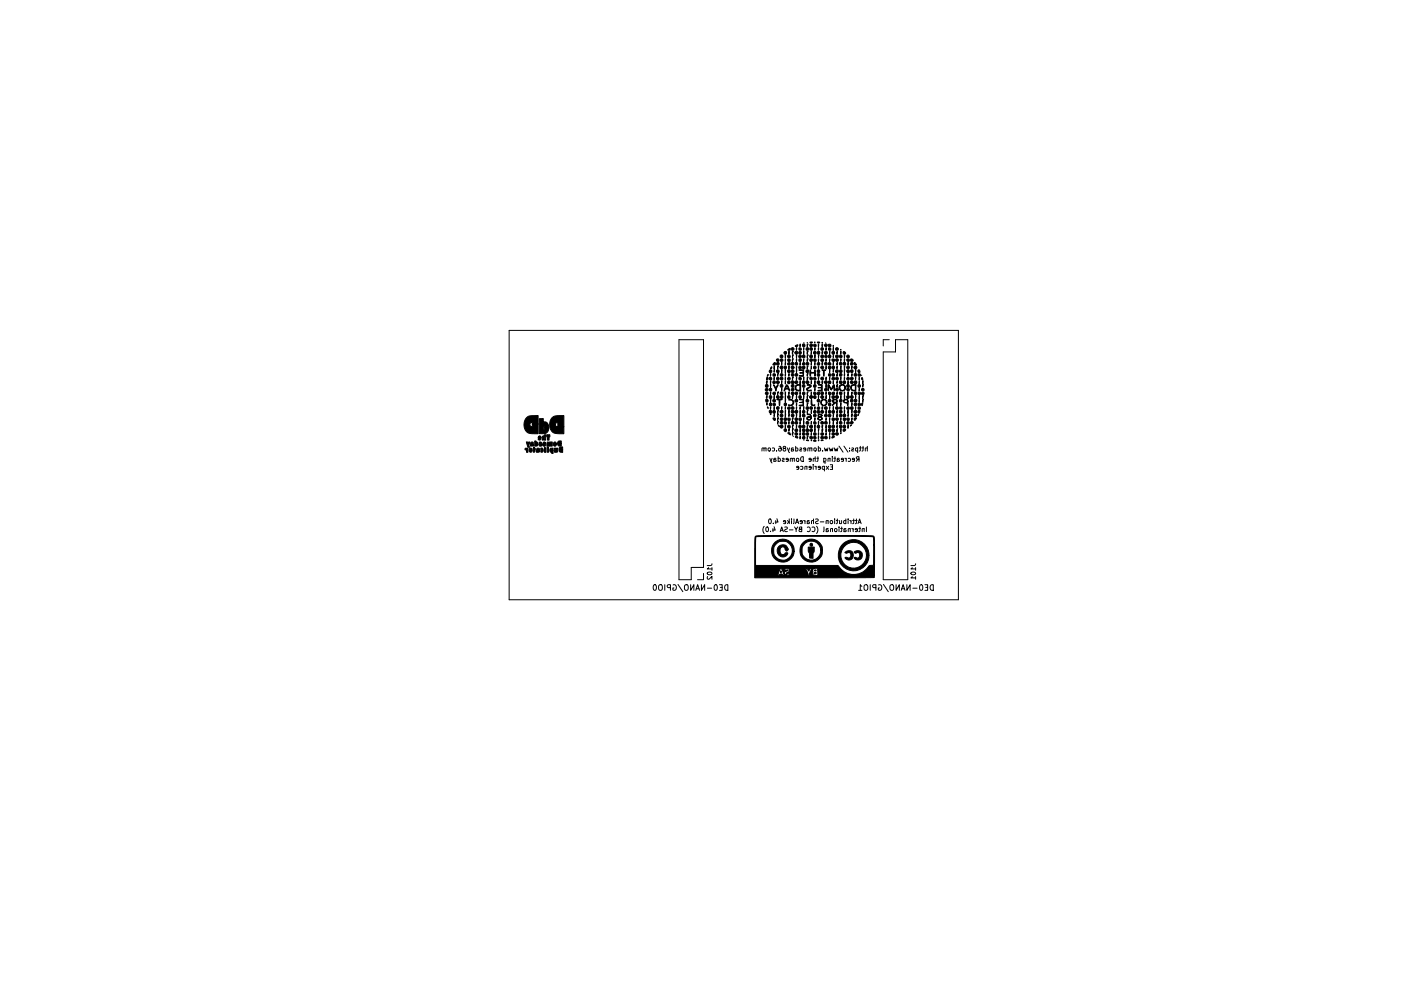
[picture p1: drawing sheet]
<svg xmlns="http://www.w3.org/2000/svg" width="297mm" height="210mm" viewBox="0 0 297 210" stroke-linecap="round" stroke-linejoin="round" font-family="sans-serif">
<g fill="none" stroke="#000" stroke-width=".21">
<path d="M107.9 70.1h95.3v57.1h-95.3zM144 72.1h5.2v48.3h-2.6v2.6h-2.6zM188.5 72.1h-1.2v1.3M189.9 72.1h2.6v50.9h-5.2v-48.3h2.6zM162 95.2l-.4-.1v.6M162.4 95.1h-.4v.6M162.4 95v.7M162.9 95.1h.4v.5h-.4zM163.2 97.2l.5 1M163.7 97.2l-.2 .7M163.7 95.1l.3-.1 .2 .2-.1 .4h-.4M164.1 97.5l.5 .2-.2 .2-.3-.1"/>
<path d="M164.5 97.3h-.4v.6M164.6 95.6v.1M165 97.3l.3-.1 .2 .2-.1 .4h-.4M165 96.9v1M165.2 94.7l.4 .2v.6l-.1 .2-.4-.1 .1-.5h.3l.1 .2M165.9 97.3l.4 .1-.4 .2v.2h.4M166.2 95.1l-.2 .2 .2 .4 .4-.1v-.3l-.5-.3v-.3l.5 .1-.2 .3M166.9 95l.5 1M167.1 97.6l-.5-.1 .1-.2 .3-.1 .1 .2v.4h-.4M167.4 95l-.2 .7M168 97.4l-.4-.1v.6M168.2 95.1l-.3-.1-.1 .2v.5h.3l.1-.3-.4-.1"/>
<path d="M168.4 97.3h-.4v.6M168.4 97.2v.7M168.7 94.7v.9h.4v-.5h-.4M168.9 97.3h.4v.5h-.4zM169.4 99.3l-.5-.1v-.2l.3-.1 .2 .2-.1 .4h-.4M169.6 95.1l.4 .1-.4 .2v.2h.4M169.7 99l.3-.1 .2 .2-.1 .4h-.4M169.8 97l.5-.1v1a.52 .52 0 0 1-.5-.3 .52 .52 0 0 1 0-.6zM170.8 95.4l-.4-.1v-.2l.3-.1 .1 .2v.4h-.4M171.1 99h-.4l-.1 .6M171.1 98.9v.7M171.7 95.2l-.4-.1v.6"/>
<path d="M172 97.6l-.5-.1 .1-.2 .2-.1 .2 .2-.1 .4h-.3M172 99.3l-.5-.1 .1-.2 .2-.1 .2 .2-.1 .4h-.3M172.1 95.1h-.4v.6M172.1 95v.7M172.4 98.6v.1M172.4 98.9v.7M172.6 95.1h.4v.5h-.4zM172.7 98.9l.3 .2M172.8 97.3h-.3l-.1 .6M172.8 96.9v1M173 98.9v.7M173.2 97.2h.4"/>
<path d="M173.4 96.9v.9l-.2 .1M173.5 94.7v.9h.4v-.5h-.4M173.9 99.3l-.4-.1v-.2l.3-.1 .1 .2v.4h-.4M174.4 95.6v.1M174.6 97.2v.8l.2 .2h.3M174.6 97.3l.3-.1 .2 .2-.1 .4h-.4M174.8 99l-.3-.1-.2 .2 .1 .4h.4M174.8 95l.2 .7 .2-.5 .2 .5 .2-.7M174.8 98.9v1M175.2 98.9l.5 .7M175.7 98.9l-.5 .7M175.8 95l.2 .7 .2-.5 .2 .5 .2-.7"/>
<path d="M176 97.3h-.4v.6M176 97.2v.7M176 98.6h.5v1h-.5M176.2 99.1h.3M176.5 96.9v.1M176.5 97.2v.7M176.8 97.2h.4M176.9 95l.2 .7 .2-.5 .2 .5 .1-.7M177 96.9v.9l-.2 .1M177.5 97.5l.5 .2-.2 .2-.3-.1M177.9 94.6l.8 1.3M177.9 97.3h-.3l-.1 .6"/>
<path d="M178.8 97.6l-.4-.1v-.2l.3-.1 .1 .2v.4h-.4M178.9 94.6l.9 1.3M179.1 97.2l.3 .2M179.4 97.2v.7M179.8 97.3l.3-.1 .2 .2-.1 .4h-.4M180.1 95.6v.1M180.1 95.1v.1M180.6 95.1l.4 .1-.4 .2v.2h.4M181.2 97.6l-.5-.1v-.2l.3-.1 .2 .2-.1 .4h-.4M181.8 95.1l-.2-.1-.2 .2 .1 .4h.3M181.8 95v1M181.9 97.4l-.3 .5"/>
<path d="M182.1 97.4h-.5v-.4l.5-.1v1M182.2 95h.4M182.4 94.7v.9l-.2 .1M182.7 95h.4M183 94.7v.9l-.3 .1M183.9 95.1h-.4v.6M183.9 94.7v1M150.9 119.6l-.1 .3-.9 .1M162 111.7a1.15 1.15 0 0 0 0 1.5M162.5 111.9l.1-.1a.49 .49 0 0 1 .4 .5 .49 .49 0 0 1-.5 .5l-.1-.4zM163.1 110.2l.1-.1a.49 .49 0 0 1 .4 .5 .49 .49 0 0 1-.5 .5l-.1-.4zM163.4 112.7v.1"/>
<path d="M163.9 112.1v.7M164 111v.1M164.1 111.8l.3 .7h-.7M164.5 110.4v.7M164.7 110.1l.3 .7h-.7M165.4 112.8l.3-1 .4 1M165.5 112.5h.5M166.4 111.9h.5a.42 .42 0 0 1-.5 .5l.1 .4h.4M166.6 110.8l-.5-.1v-.2l.3-.1 .2 .2-.1 .5h-.4M167 110.4l.3 .4M167.2 110.7l-.2 .4M167.3 110.1v1"/>
<path d="M167.4 112.4h.7M167.8 110.1v.1M167.8 110.4v.7M168.3 110.1v.9l-.1 .1M168.5 111.8l.3 .5 .3-.5M168.7 111.1l.3-1 .3 1M168.8 110.8h.4M168.8 112.3v.5M169.6 112.3l-.2 .2 .2 .3h.4v-1l-.5 .1 .1 .3 .4 .1M170.1 110.8l-.5-.1 .1-.2 .3-.1 .1 .2v.5h-.4M170.4 110.4l.3 .2M170.7 110.4v.7"/>
<path d="M171.1 110.7l.5 .2-.1 .2h-.4M171.2 111.9a.44 .44 0 0 1 .6 .4 .44 .44 0 0 1-.6 .4M171.6 110.5h-.4l-.1 .6M172.2 111.9a.44 .44 0 0 1 .6 .4 .44 .44 0 0 1-.6 .4M172.5 110.5h-.4v.6M172.5 110.1v1M172.9 110.2h.5a.42 .42 0 0 1-.4 .5v.4h.5M173.1 111.7a1.15 1.15 0 0 1 0 1.5M173.9 110.7h.8M174.7 111.8v.9l-.1 .1M175.2 112.4l.4 .2-.1 .2h-.3M175.6 110.5h-.4l-.1 .6"/>
<path d="M175.6 110.4v.7M175.6 112.2h-.4v.6M176.1 110.5h.4l-.1 .6-.3-.1zM176.5 112.2h-.4v.6M176.5 112.1v.7M177 110.1v.1M177 110.4v.7M177 112.2h.4v.6l-.4-.1zM177.3 110.4h.4M177.5 110.1v.9l-.2 .1M177.9 111.8v.1M177.9 112.1v.7"/>
<path d="M178 110.4v.7M178.2 112.1h.4M178.4 110.4v.7l-.4-.1M178.5 111.8v.9l-.3 .1M178.9 112.4l.5 .2-.1 .2h-.4M179.3 110.5l-.2-.1-.2 .2 .1 .5h.3M179.3 110.1v1M179.4 112.2h-.4l-.1 .6M179.8 110.1v.1M179.8 110.4v.7M180.1 110.4l.3 .2M180.3 112.2h-.4l-.1 .6"/>
<path d="M180.3 112.1v.7M180.4 110.4v.7M180.6 112.1l.3 .2M180.8 110.4h.3M180.9 112.1v.7M181 110.1v.9l-.2 .1M181.3 110.4h.4M181.6 110.1v.9l-.3 .1M181.8 112.5l-.5-.1 .1-.2 .2-.1 .2 .2-.1 .5h-.3M181.9 111.1l.3-1 .4 1M182 110.8h.5M182.1 112.1h.4"/>
<path d="M182.3 111.8v.9l-.2 .1M183.2 112.2h-.4v.6M183.2 112.1v.7M183.7 111.8v1M194.1 119.6l-.1 .3-.9 .1M138.6 124.2l.2-.1a.64 .64 0 0 1 .4 .6 .64 .64 0 0 1-.4 .6l-.3-.5zM139.7 124.2l.2-.1a.4 .4 0 0 1 .5 .4v.4a.4 .4 0 0 1-.4 .4 .4 .4 0 0 1-.4-.4zM140.9 124.1v1.2M142.1 124.7l-.5-.1-.1-.4 .6-.1v1.2M142.7 124.1a.55 .55 0 0 1 .7 .6 .55 .55 0 0 1-.7 .4v-.4h.2M143.7 124l1.1 1.5M145.2 124.2l.2-.1a.4 .4 0 0 1 .5 .4v.4a.4 .4 0 0 1-.4 .4 .4 .4 0 0 1-.4-.4z"/>
<path d="M146.4 124.1v1.2l.7-1.2v1.2M147.5 125.3l.4-1.2 .4 1.2M147.6 124.9h.6M148.7 124.1v1.2l.7-1.2v1.2M149.2 121.7v1.3h-1.3M150 124.8h.9M150 121.5a.49 .49 0 0 1 .6-.2 .49 .49 0 0 1 .3 .5 .49 .49 0 0 1-.6 .2 .49 .49 0 0 1-.3-.5zM150 122.3l-.1 .4 .3 .2 .7-.6v.6M150.2 120.4l-.3 .3h1M150.9 120.4v.6M151.5 124.2l.2-.1a.64 .64 0 0 1 .4 .6 .64 .64 0 0 1-.4 .6l-.3-.5zM152.5 124.1h.6v1.2h-.6"/>
<path d="M152.7 124.6h.4M153.7 124.2l.6-.1v1.2a.63 .63 0 0 1-.6-.4 .63 .63 0 0 1 0-.7zM182 125.3h.7M182.7 124.4l-.3-.3v1.2M183.2 124.2l.3-.1a.4 .4 0 0 1 .5 .4v.4a.4 .4 0 0 1-.4 .4 .4 .4 0 0 1-.4-.4zM184.5 124.1v1.2M185.7 124.7l-.6-.1v-.4l.6-.1v1.2M186.3 124.1a.55 .55 0 0 1 .7 .6 .55 .55 0 0 1-.8 .4v-.4h.2M187.3 124l1 1.5M188.7 124.2l.3-.1a.4 .4 0 0 1 .5 .4v.4a.4 .4 0 0 1-.4 .4 .4 .4 0 0 1-.4-.4zM190 124.1v1.2l.7-1.2v1.2M191.1 125.3l.4-1.2 .4 1.2"/>
<path d="M191.2 124.9h.6M192.3 124.1v1.2l.7-1.2v1.2M193.2 121.5a.49 .49 0 0 1 .5-.2 .49 .49 0 0 1 .4 .5 .49 .49 0 0 1-.6 .2 .49 .49 0 0 1-.3-.5zM193.4 120.4l-.3 .3h1M193.4 122.3l-.3 .3h1M193.5 124.8h.9M194.1 120.4v.6M194.1 122.3v.6M195.1 124.2l.1-.1a.64 .64 0 0 1 .5 .6 .64 .64 0 0 1-.5 .6l-.2-.5zM196.1 124.1h.6v1.2h-.6M196.3 124.6h.4M197.3 124.2l.6-.1v1.2a.63 .63 0 0 1-.7-.4 .63 .63 0 0 1 .1-.7z"/>
</g>
<g fill="#000" stroke="#000" stroke-width=".21">
<path d="M162.8 79.4l-.1 .4zM163.4 79.2v.6zM163.5 77.9l.1-.1v.3l-.3 .2zM164.1 77.7v.7zM164.2 78.4l-.1 .6zM164.1 77l.2-.1 .1 .5h-.5zM164.9 79.3h.2l-.2 .5zM164.9 77.7h.2l-.2 .6zM165.8 76.9l-.1 .6zM165.7 78.4v.7zM166.5 79.2v.6zM166.5 76.9v.6z"/>
<path d="M166.5 76.1v.6zM166.5 78.4v.7zM166.5 75.3v.7zM167.1 75.4h.4l-.1 .5-.4-.1zM167.1 77h.4v.4l-.5-.1zM167.3 79.2l-.1 .6zM167.3 77.7v.7zM167.3 74.5v.7zM167.1 74.2l.4-.3v.4h-.4zM168 76.2l.2-.1-.2 .6zM168 74.5h.2l-.2 .7zM168.1 75.3h.1l-.2 .7z"/>
<path d="M168.9 76.1v.6zM168.9 73.7v.6zM168.9 77.6v.7zM168.9 78.4v.7zM168.9 75.3v.7zM168.6 73.4l.5-.3a.31 .31 0 0 1-.1 .4 .31 .31 0 0 1-.4-.1zM169.4 78.5h1v1.3h-1l.8-.2v-.4l-.7-.1 .6-.1 .2-.3zM169.4 76.2l.5 .1-.1 .4-.4-.1zM169.7 76.9l-.1 .6zM169.7 73l-.1 .6zM170.2 75.4h.4v.5l-.4-.1zM170.2 77h.4v.4l-.5-.1z"/>
<path d="M170.4 76.1v.6zM170.4 73.7v.6zM170.4 72.8h.1zM170.4 74.5v.7zM171.1 72.7l.1 .1zM171.2 79.3h.1l-.1 .5zM171.2 76.2l.1-.1-.1 .6zM171.2 73h.1l-.1 .6zM171.2 77.7h.1l-.1 .6zM171.2 74.5h.1l-.1 .7zM171.2 75.3h.2l-.2 .7zM171.8 78.5a.5 .5 0 0 0 .5 .5 .5 .5 0 0 0 .5-.5v1.3l-.1-.6h-.8l-.1 .6z"/>
<path d="M171.8 72.6h.5l-.3 .2zM172 76.9v.6zM172 77.6v.7zM172 74.5v.7zM172.8 76.9v.6zM172.8 73.7v.6zM172.7 72.5l.1 .3zM172.8 75.3v.7zM173.3 72.6l.5 .1-.3 .1zM173.4 77h.3v.4l-.4-.1zM173.5 76.1v.6zM173.5 73.7v.6z"/>
<path d="M173.5 73v.6zM173.5 77.7v.7zM173.6 75.3l-.1 .6zM174.2 72.7h.2zM174.3 76.9h.1l-.1 .6zM174.3 73.1h.1l-.1 .5zM174.3 74.6l.1-.1v.2l-.1 .4zM174.3 78.5h.8l-.3 .1-.1 1.2-.1-1.2zM175.2 76.1l-.1 .6zM175.2 73.7l-.1 .6zM175.1 77.7v.7zM175.9 76.1v.6z"/>
<path d="M175.9 78.4v.7zM175.9 74.5v.7zM176.6 73.3l.1 .2zM176.7 76.9v.6zM176.7 73.8v.6zM176.7 78.4v.6zM176.7 75.3v.6zM177.5 77.7l.1-.1-.1 .6zM177.5 74.6l.1-.1-.1 .6zM177.5 79.3v.5zM177.5 76.9v.6zM178.3 76.1v.6z"/>
<path d="M178.3 74.5v.7zM178.3 74.1v.2zM178.3 77.7v.7zM179.1 79.2l-.1 .6zM179.1 76.1l-.1 .6zM179 78.4v.7zM179 77.7v.7zM179 75.3v.7zM179.8 79.2v.6zM179.8 76.9v.6zM180.6 79.3v.5zM180.6 77.7v.5z"/>
<path d="M181.2 76.9l.4 .5h-.4zM181.4 78.4v.7zM182 78.5l.3 .1v.4l-.1 .1-.3-.2zM111.6 93.8h.3l.1 .2 .3-.2-.2 .7 .2 .4h-.4zM111.3 95.2l.6-.1v.9h-.3v-.5a.21 .21 0 0 1-.2-.1 .21 .21 0 0 1-.1-.2zM112.3 95.2l.3-.1 .2 .2v.2l-.3-.1v.2l.3-.1a.37 .37 0 0 1-.5 .4 .37 .37 0 0 1-.1-.6zM112.6 93.9a.28 .28 0 0 1 .3-.1 .28 .28 0 0 1 .2 .3l-.3 .1 .3 .2h-.3h.3v.2h-.6zM113.2 94.8l.3 .5a.44 .44 0 0 1-.4 .6l-.1-.7zM111.7 88.6a1.75 1.75 0 0 1 1.5-.4h.9v1.8h-1.2l-.1-.3a.39 .39 0 0 0-.5 .4 .39 .39 0 0 0 .5 .3l.1-.4h1.2v2a3.1 3.1 0 0 1-2.6-.5 2.32 2.32 0 0 1 .2-2.9zM113.4 93.6h.2l.1 .2 .3 .1 .1 .4-.4-.2v.3l.4-.1-.2 .3-.5 .1zM113.9 95.1a.29 .29 0 0 1 .3 0 .29 .29 0 0 1 .2 .3h-.3l.3 .3h-.3h.3l-.1 .2-.6 .1zM114.2 92.6l.3-.1 .2 .2-.4 .1h.4a.35 .35 0 0 1-.1 .5 .35 .35 0 0 1-.5-.2h.3l-.3-.2z"/>
<path d="M114.3 93.8a.33 .33 0 0 1 .5 .1 .33 .33 0 0 1-.2 .5h.2a.3 .3 0 0 1-.3 .3 .3 .3 0 0 1-.3-.4 .3 .3 0 0 1 .4-.2zM114.7 95.1a.42 .42 0 0 1 .5 .4 .42 .42 0 0 1-.5 .4l-.1-.3 .3-.1a.21 .21 0 0 1-.3-.2 .21 .21 0 0 1 .1-.2zM114.3 88.8h.9v.8a.95 .95 0 0 1 1.2 1.2h-.9l-.2-.3-.1 .6h.2l.1-.3h.9a1.18 1.18 0 0 1-1.5 1.2h-.6zM115.3 93.8h.2l.2 .3-.4-.1v.1h.4a.35 .35 0 0 1-.1 .5 .35 .35 0 0 1-.5-.2l.3-.1h-.3zM115.4 95.1h.3v.9h-.3zM115 92.5l.4 .1v-.3l.3-.1v1.2h-.3l-.1-.7-.1 .7h-.2zM115.5 94.9h.1l-.1 .1zM115.9 92.2h.7l-.2 1.2h-.3zM116 94.8h.3v1.1h-.3zM116.1 93.8l.3 .1 .7-.1v.9h-.3l-.1-.7-.1 .7h-.2l-.1-.7-.1 .7h-.2zM116.7 95.1h.6v.4l-.4-.1v.1v.2l.4-.2v.7h-.3v-.2a.5 .5 0 0 1-.4-.3 .5 .5 0 0 1 .1-.6zM117.5 93.8l.4 .1 .1 .3-.4-.1v.1h.4v.1a.37 .37 0 0 1-.6 .3 .37 .37 0 0 1 0-.6z"/>
<path d="M117.5 95.1h.4v.6l.1-.6h.2l-.1 .8h-.5zM118.3 93.7l.7-.1v.5l-.4-.1-.1 .1 .1 .1 .4-.1v.6a.6 .6 0 0 1-.7-.3 .6 .6 0 0 1 0-.7zM117.1 88.6a2.99 2.99 0 0 1 2.4-.4v2.4h-1.2v-.9a.42 .42 0 0 0-.5 .5 .42 .42 0 0 0 .5 .4h1.2v1.4a3.2 3.2 0 0 1-2.5-.5 2.39 2.39 0 0 1 .1-2.9zM118.6 95l.7-.2v.6h-.3l-.1-.2-.1 .2 .1 .1 .1-.1h.3v.6l-.4-.1a.58 .58 0 0 1-.3-.9zM162.6 85.6v-.1v.5zM162.6 83.9v.6zM162.6 80.8v.6zM162.6 80l.2 .2 .1 .2-.3 .2-.1-.1zM162.7 86.3l.1 .4zM163.2 85.6l.4 .1-.1 .4-.4-.1zM163.2 82.4l.4 .1-.1 .4h-.4zM163.3 87.9h.2z"/>
<path d="M163.4 86.3v.6zM163.4 83.1v.6zM163.4 84.7v.7zM163.4 81.5v.7zM163.4 80.8v.7zM163.9 88.7h.4l.1 .4-.3 .1zM164 84.8h.3v.5l-.4-.1zM164 83.2h.3v.5l-.4-.1zM164.2 80l-.1 .6zM164.1 86.3v.6zM164.1 83.9v.7zM164.2 87.8l-.1 .6z"/>
<path d="M164 81.6l.5 .7 .3-.6h.2l-.5 1.3zM164.9 89.4h.2l-.2 .6zM164.9 88.7h.2l-.2 .5zM164.9 83.2h.2l-.2 .5zM165 87.8l.1 .1-.2 .6zM164.9 87.1l.2-.1-.2 .8zM164.7 84.8h1.2h-.5l-.1 1.3-.1-1.3zM165 90.2l.2 .3zM165.8 86.3l-.1 .6zM165.8 82.4l-.1 .6zM165.8 80.8l-.1 .6zM166.3 88.7l.5 .1-.1 .4-.4-.1z"/>
<path d="M166.3 85.6l.5 .1-.1 .4-.4-.1zM166.5 86.3v.6zM166.5 83.1v.6zM166.5 80v.6zM166.5 90.2v.7zM166.5 87.8v.7zM166.5 87.1v.7zM166.5 84.7v.7zM166.5 83.9v.7zM166.5 80.8v.7zM166.8 81.7l-.2 .6 .5 .1-.2-.7 .5 1.3a.6 .6 0 0 0-.6-.5 .6 .6 0 0 0-.6 .5zM167.1 91.8l.4 .1 .1 .4-.5-.3z"/>
<path d="M167.1 86.4h.4v.4l-.5-.1zM167.1 80.1h.4v.5l-.5-.1zM167.3 89.4l-.1 .6zM167.3 83.1l-.1 .6zM167.3 87.1v.7zM167.2 84.8a.69 .69 0 0 1 .9 .1 .69 .69 0 0 1 0 1 .69 .69 0 0 1-1 0 .61 .61 0 0 0 1-.5 .61 .61 0 0 0-.9-.5zM167.3 91v.5zM167.3 87.8v.6zM168 91.8h.2l-.2 .6zM168 88.7h.2l-.2 .5zM168 80.1l.2-.1-.2 .6zM168 83.9h.2l-.2 .7z"/>
<path d="M168.1 90.9l.1 .1-.2 .6zM168 90.2h.2l-.2 .7zM168.6 92.6h.3l.2 .3h-.3zM168.9 86.3v.6zM168.9 85.5v.6zM168.9 80v.6zM168.9 90.2v.6zM168.9 83.9v.7zM168.9 87.8v.7zM168.7 81.8l.6-.2 .5 .1a.63 .63 0 0 0-.9 .2 .63 .63 0 0 0 .2 .9h.5v-1.1h.2v1.3l-.5-.1a.69 .69 0 0 1-.7-.3 .69 .69 0 0 1 .1-.8zM169.7 92.5l-.1 .6zM169.7 91.8l-.1 .6z"/>
<path d="M169.7 89.4l-.1 .6zM169.7 86.3l-.1 .6zM169.7 83.1l-.1 .6zM169.6 90.9v.7zM169.6 87.8v.7zM169.6 87.1v.7zM169.6 80.8v.7zM169.4 84.8l1-.1v1.4l-1-.1 .8-.1 .1-.2-.2-.3h-.6l.7-.2v-.3zM170.2 91l.4 .1v.4h-.4zM170.2 92.6h.4v.5l-.5-.1zM170.2 83.2h.4v.5l-.5-.1zM170.4 88.6v.6z"/>
<path d="M170.4 82.4v.6zM170.4 93.3l.1 .1zM170.4 89.4v.6zM170.4 86.3v.6zM170.4 80v.6zM170.4 83.9v.7zM171 93.4l.4 .1zM171.2 92.6h.1l-.1 .5zM171.2 85.6l.1-.1-.1 .6zM171.2 83.2h.1l-.1 .5zM171.2 80.1l.1-.1-.1 .6zM171.2 83.9h.1l-.1 .7z"/>
<path d="M171.2 90.2h.2l-.2 .7zM171.2 87.1l.2-.1-.2 .8zM171.1 81.7l.4-.1 .5 .2-.1 .3-.7 .5 .1 .2h.7l-.6 .1-.4-.2 .1-.3 .7-.6zM171.1 87.9a.63 .63 0 0 1 .7 .1 .63 .63 0 0 1 .2 .7l-.6-.2-.2 .4 .4 .1 .2-.3h.2a.5 .5 0 0 1-.5 .4 .5 .5 0 0 1-.5-.3l.3-.4 .6-.1a.54 .54 0 0 0-.8-.3zM172 93.3v.2zM172 91.8v.6zM172 89.4v.6zM172 83.1v.6zM172 80.8v.6zM172 87.1v.7zM172 84.7l.2 1.2h.6l-.4 .2a.9 .9 0 0 1-.4-1.4zM172.6 93.4h.3l.1 .1-.5 .1z"/>
<path d="M172.8 88.6v.6zM172.8 86.3v.6zM172.8 82.4v.6zM172.8 90.9v.7zM172.8 90.2v.7zM172.8 80.8v.7zM173.4 84.8h.3v.5l-.4-.1zM173.4 86.4h.3v.4l-.4-.1zM173.4 83.2h.3v.5l-.4-.1zM173.5 93.3v.2zM173.5 92.5v.6zM173.5 91.8v.6z"/>
<path d="M173.5 85.5v.6zM173.5 89.4v.6zM173.5 80v.6zM173.5 83.9v.7zM173.6 91l-.1 .5zM173.5 88a.52 .52 0 0 1 .8 .1l-.5-.2-.2 .3 .2 .2 .5-.3-.2 .4 .3 .3-.2-.1a.34 .34 0 0 0-.4-.1 .34 .34 0 0 0-.2 .4h.4l.4-.2a.55 .55 0 0 1-.5 .3 .55 .55 0 0 1-.6-.3l.2-.3zM173.5 81.6h.8v1.4l-.9-.1a.62 .62 0 0 0 .8-.4l-.2-.2h-.6l.7-.2a.45 .45 0 0 0-.1-.4 .45 .45 0 0 0-.5-.1zM174.1 93.4h.5l-.4 .1zM174.3 86.3h.1l-.1 .6zM174.3 90.2h.1v.1l-.1 .5zM174.3 80.8h.1v.1l-.1 .5zM174.1 85a.69 .69 0 0 1 .8-.3 .69 .69 0 0 1 .4 .7h-.1a.51 .51 0 0 0-.7-.4 .51 .51 0 0 0-.3 .7 .51 .51 0 0 0 .8 .1l.2-.4h.1a.7 .7 0 0 1-.9 .7 .7 .7 0 0 1-.3-1.1z"/>
<path d="M174.3 91h.2l-.2 .6zM175.2 91.8l-.1 .6zM175.2 88.6l-.1 .6zM175.2 83.1l-.1 .6zM175.2 80l-.1 .6zM175.2 90.2l-.1 .6zM175.1 90.9v.7zM175.1 87.1v.7zM175.1 83.9v.7zM175.1 81.5v.7zM175.9 92.5v.6zM175.9 91.8v.6z"/>
<path d="M175.9 89.4v.6zM175.9 88.6v.6zM175.9 86.3v.6zM175.9 80v.6zM175.9 83.9v.7zM176.5 83.2h.4v.5l-.5-.1zM176.5 80.1h.4v.5l-.5-.1zM176.4 92.7l.4-.2 .1 .1-.4 .3zM176.7 89.4v.6zM176.7 86.3v.6zM176.7 80.8v.7zM175.6 81.6l.2 .2 .4 .7 .5-.8 .2-.1v1.3l-.2-1.1-.4 1-.6-1.1-.1 1.2z"/>
<path d="M176.7 87.8v.6zM176.6 84.8l.7-.1 .2 .4a.47 .47 0 0 0-.8 0 .48 .48 0 0 0 .8 0v1l-.2-.6h-.1l-.7 .6 .3-.6-.3-.3zM177.5 87.8l.1 .1-.1 .6zM177.5 81.6h.1l-.1 .6zM177.5 90.2h.1l-.1 .6zM177.5 87.1l.1-.1-.2 .7zM177.5 90.9v.7zM177.5 89.4v.6zM177.5 83.2v.5zM177.5 80.8v.6zM178.2 91.8h.1v.2zM178.3 88.6v.6z"/>
<path d="M178.3 85.5v.6zM178.3 80v.6zM178.3 90.9v.7zM178.3 83.9v.7zM178.1 81.8l.7-.2 .5 .4v.2h-.2a.53 .53 0 0 0-.8-.4 .53 .53 0 0 0-.1 .8 .53 .53 0 0 0 .9-.1v-.3h.2a.72 .72 0 0 1-.9 .7 .72 .72 0 0 1-.3-1.1zM178.8 91.1l.4-.1 .1 .3-.5 .2zM179.1 89.4l-.1 .6zM179.1 86.3l-.1 .6zM179.1 83.1l-.1 .6zM179.1 80l-.1 .6zM179 87.1v.7zM179 83.9v.7z"/>
<path d="M178.8 84.9l.9-.2 .1 .4h-.1a.37 .37 0 0 0-.4-.3 .37 .37 0 0 0-.4 .4l.5 .2 .4-.3-.1 1-.1-.6a.6 .6 0 0 1-.8-.4zM179.6 89.5h.4v.4h-.5zM179.6 86.4h.4v.4l-.5-.1zM179.6 80.1h.4v.5l-.5-.1zM179.8 83.2v.6zM179.8 90.2v.7zM179.8 87.1v.7zM179.8 80.8v.7zM179.8 87.8v.6zM180.3 90.3l.2-.1zM180.6 87.1l.1-.1v.2l-.1 .5zM180.6 87.8v.7z"/>
<path d="M180.6 88.7v.5zM180.6 85.5v.6zM180.6 83.2v.5zM180.5 81.8l.6-.2 .4 .1a.62 .62 0 0 0-1 .4 .62 .62 0 0 0 .9 .7v-1.1h.1l-.1 1.2a.74 .74 0 0 1-.9-.2 .74 .74 0 0 1 0-.9zM181.2 88.7h.4l-.4 .5-.1-.3zM181.4 86.3v.6zM181.4 80v.6zM181.4 83.9v.7zM181.9 87.9h.2l-.2 .3zM182.2 82.4v.6zM182.2 80v.6zM182 87.1h.3l-.1 .6-.3-.2z"/>
<path d="M182.2 84.7v.7zM182.2 83.9v.7zM182.2 80.8v.7zM182.7 80.1l.2 .1v.4l-.2-.1zM182.7 85.6h.2l-.1 .5zM182.8 83.2h.3v.5l-.4-.1zM182.9 80.8v.7zM182.9 83.9h.2l-.2 .7zM183 84.7l.1 .1-.2 .6zM183 81.6l-.1 .5zM164.4 115a2.41 2.41 0 0 1 2.6-.4 2.41 2.41 0 0 1 1.4 2.4h-.4a2.02 2.02 0 0 0-2.7-2.1 2.02 2.02 0 0 0-.7 3.4 2.02 2.02 0 0 0 3.3-.8l.1-.5h.4a2.42 2.42 0 0 1-3.5 2 2.42 2.42 0 0 1-.5-4zM165.1 115.9a1.16 1.16 0 0 1 1.2-.3 1.16 1.16 0 0 1 .8 1l-.3 .3-.4-.5a.48 .48 0 0 0-.6-.4 .94 .94 0 0 0 .1 1.7l.5-.2 .1-.2h.5a1.12 1.12 0 0 1-1.2 .9 1.12 1.12 0 0 1-1-1.1v-.5z"/>
<path d="M160.2 113.8l3.8-.2 20.8 .1h.4l.1 .3 .1 1.6h-.2v-1.4a.46 .46 0 0 0-.3-.4 .46 .46 0 0 0-.4 0l-24.1 .1a2.21 2.21 0 0 0-.2 1.6v4.5h17.5a3.8 3.8 0 0 0 6.6 0l.9-.1v-4.3h.2v6.5h-12l-.1-1.3-.2-.2h-1.1l-.5 .6-.3-.5-.4-.1 .5 1.1h-3.8l-.1-.1-.7 .2v-.2l.6-.3a.46 .46 0 0 0-.3-.7 .46 .46 0 0 0-.5 .5l.4-.2 .2 .1a.81 .81 0 0 0-.8 .8l.5 .3h-.5l-.7-1.5-.4 .6-.3 .8 .1 .1a.61 .61 0 0 1 .6-.4 .61 .61 0 0 1 .5 .4h.9l.5-.4h3.8l.2 .4 .6-1.5h.5l-.4 .3 .2 .3a.54 .54 0 0 0-.1 .7 .54 .54 0 0 0 .7 .2h12.4v.4h-.4l-25 .1v-7.8zM171.4 116.1h1.2l-.2 2.4-.7-.1zM170.3 115.1a2.36 2.36 0 0 1 2.6-.6 2.36 2.36 0 0 1 1.5 2.2h-.4a1.99 1.99 0 0 0-2.9-1.6 1.99 1.99 0 0 0-.2 3.3 1.99 1.99 0 0 0 3.1-1.2v-.5h.4a2.42 2.42 0 0 1-3.3 2.4 2.42 2.42 0 0 1-.8-4zM179.1 117.2a.98 .98 0 0 1 1.5-.2 .98 .98 0 0 1 0 1.5 .98 .98 0 0 1-1.4-.1l.3-.2a.56 .56 0 0 0 .8 0 .56 .56 0 0 0-.1-.8 .56 .56 0 0 0-.7 0zM178.9 115.2a3.3 3.3 0 0 1 3.5-.4 3.3 3.3 0 0 1 1.8 3h-.5a2.72 2.72 0 0 0-3.8-2.5 2.72 2.72 0 0 0-.6 4.6 2.72 2.72 0 0 0 4.3-1.5l.1-.6h.5a3.3 3.3 0 0 1-4.7 3 3.3 3.3 0 0 1-.6-5.6zM181.1 117.1a.98 .98 0 0 1 1.5 0 .98 .98 0 0 1-.1 1.4 .98 .98 0 0 1-1.4-.1l.3-.2a.6 .6 0 0 0 .9-.2 .6 .6 0 0 0-.5-.8l-.3 .2-.3-.1zM165.5 121.1l.2 .3-.1 .1zM172.7 121h.4l-.3 .1zM172.6 121.5l.4-.1 .1 .2-.5 .1z"/>
<circle cx="163.4" cy="78.8" r=".3"/>
<circle cx="164.1" cy="79.5" r=".3"/>
<circle cx="164.9" cy="77.2" r=".3"/>
<circle cx="164.9" cy="78.8" r=".31"/>
<circle cx="164.9" cy="76.4" r=".3"/>
<circle cx="165.7" cy="78" r=".3"/>
<circle cx="165.7" cy="75.6" r=".31"/>
<circle cx="165.7" cy="76.4" r=".3"/>
<circle cx="165.7" cy="79.5" r=".3"/>
<circle cx="166.5" cy="78" r=".3"/>
<circle cx="166.5" cy="74.9" r=".29"/>
<circle cx="167.2" cy="78.8" r=".3"/>
<circle cx="167.3" cy="76.4" r=".3"/>
<circle cx="168" cy="77.2" r=".3"/>
<circle cx="168" cy="79.5" r=".3"/>
<circle cx="168.1" cy="78.7" r=".32"/>
<circle cx="168.1" cy="74" r=".31"/>
<circle cx="168.1" cy="78" r=".34"/>
<circle cx="168.8" cy="74.8" r=".3"/>
<circle cx="168.8" cy="79.5" r=".3"/>
<circle cx="168.8" cy="77.2" r=".3"/>
<circle cx="169.6" cy="74.8" r=".3"/>
<circle cx="169.6" cy="78" r=".3"/>
<circle cx="169.6" cy="75.6" r=".3"/>
<circle cx="169.6" cy="74" r=".3"/>
<circle cx="170.4" cy="78" r=".31"/>
<circle cx="170.4" cy="73.3" r=".31"/>
<circle cx="171.2" cy="78.8" r=".31"/>
<circle cx="171.2" cy="74" r=".3"/>
<circle cx="171.2" cy="77.2" r=".31"/>
<circle cx="172" cy="75.6" r=".31"/>
<circle cx="172" cy="76.4" r=".3"/>
<circle cx="172" cy="73.3" r=".3"/>
<circle cx="172" cy="74" r=".3"/>
<circle cx="172.7" cy="74.8" r=".3"/>
<circle cx="172.7" cy="78" r=".3"/>
<circle cx="172.8" cy="73.3" r=".3"/>
<circle cx="172.8" cy="76.4" r=".3"/>
<circle cx="173.5" cy="74.9" r=".31"/>
<circle cx="173.5" cy="78.8" r=".3"/>
<circle cx="173.5" cy="79.5" r=".31"/>
<circle cx="174.3" cy="75.6" r=".31"/>
<circle cx="174.3" cy="74" r=".31"/>
<circle cx="174.3" cy="78" r=".31"/>
<circle cx="174.3" cy="76.4" r=".3"/>
<circle cx="175.1" cy="73.3" r=".3"/>
<circle cx="175.1" cy="74.8" r=".31"/>
<circle cx="175.1" cy="77.2" r=".3"/>
<circle cx="175.1" cy="75.6" r=".3"/>
<circle cx="175.9" cy="78" r=".3"/>
<circle cx="175.9" cy="75.6" r=".3"/>
<circle cx="175.9" cy="73.3" r=".3"/>
<circle cx="175.9" cy="74" r=".3"/>
<circle cx="175.9" cy="77.2" r=".3"/>
<circle cx="175.9" cy="79.5" r=".3"/>
<circle cx="176.6" cy="74.9" r=".31"/>
<circle cx="176.6" cy="78" r=".31"/>
<circle cx="176.7" cy="79.5" r=".31"/>
<circle cx="176.7" cy="76.4" r=".28"/>
<circle cx="177.4" cy="78.8" r=".31"/>
<circle cx="177.4" cy="76.4" r=".29"/>
<circle cx="177.5" cy="75.6" r=".31"/>
<circle cx="177.5" cy="74" r=".31"/>
<circle cx="178.2" cy="79.5" r=".3"/>
<circle cx="178.2" cy="77.2" r=".3"/>
<circle cx="178.3" cy="78.8" r=".3"/>
<circle cx="178.3" cy="75.6" r=".3"/>
<circle cx="179" cy="74.9" r=".31"/>
<circle cx="179" cy="77.2" r=".3"/>
<circle cx="179.8" cy="78.8" r=".3"/>
<circle cx="179.8" cy="75.6" r=".3"/>
<circle cx="179.8" cy="78" r=".31"/>
<circle cx="179.8" cy="76.4" r=".28"/>
<circle cx="180.6" cy="78.7" r=".3"/>
<circle cx="180.6" cy="76.4" r=".31"/>
<circle cx="180.6" cy="77.2" r=".31"/>
<circle cx="181.4" cy="79.5" r=".3"/>
<circle cx="181.4" cy="78" r=".31"/>
<circle cx="182.2" cy="79.5" r=".3"/>
<circle cx="162.6" cy="81.9" r=".31"/>
<circle cx="162.6" cy="83.4" r=".31"/>
<circle cx="162.6" cy="82.7" r=".3"/>
<circle cx="162.6" cy="85" r=".32"/>
<circle cx="163.3" cy="84.2" r=".32"/>
<circle cx="163.4" cy="87.3" r=".3"/>
<circle cx="163.4" cy="80.3" r=".31"/>
<circle cx="164.1" cy="81.1" r=".3"/>
<circle cx="164.1" cy="87.4" r=".3"/>
<circle cx="164.1" cy="85.8" r=".3"/>
<circle cx="164.9" cy="84.2" r=".31"/>
<circle cx="164.9" cy="86.6" r=".3"/>
<circle cx="164.9" cy="80.3" r=".29"/>
<circle cx="164.9" cy="81.1" r=".33"/>
<circle cx="165.7" cy="81.9" r=".31"/>
<circle cx="165.7" cy="88.2" r=".31"/>
<circle cx="165.7" cy="80.3" r=".31"/>
<circle cx="165.7" cy="89.7" r=".31"/>
<circle cx="165.7" cy="83.4" r=".31"/>
<circle cx="165.7" cy="90.5" r=".31"/>
<circle cx="165.7" cy="84.2" r=".31"/>
<circle cx="165.7" cy="87.4" r=".31"/>
<circle cx="165.7" cy="88.9" r=".3"/>
<circle cx="166.5" cy="89.7" r=".3"/>
<circle cx="166.5" cy="91.3" r=".28"/>
<circle cx="167.2" cy="81.1" r=".3"/>
<circle cx="167.2" cy="84.2" r=".3"/>
<circle cx="167.3" cy="88.9" r=".3"/>
<circle cx="167.3" cy="90.5" r=".32"/>
<circle cx="168" cy="88.2" r=".3"/>
<circle cx="168.1" cy="82.7" r=".29"/>
<circle cx="168.1" cy="81.9" r=".31"/>
<circle cx="168.1" cy="83.4" r=".31"/>
<circle cx="168.1" cy="86.6" r=".31"/>
<circle cx="168.1" cy="89.7" r=".31"/>
<circle cx="168.1" cy="81.1" r=".34"/>
<circle cx="168.1" cy="87.3" r=".33"/>
<circle cx="168.8" cy="89.7" r=".31"/>
<circle cx="168.8" cy="83.4" r=".31"/>
<circle cx="168.8" cy="85" r=".3"/>
<circle cx="168.8" cy="91.3" r=".3"/>
<circle cx="168.8" cy="81.1" r=".3"/>
<circle cx="168.8" cy="92.1" r=".31"/>
<circle cx="168.8" cy="88.9" r=".31"/>
<circle cx="168.8" cy="87.4" r=".31"/>
<circle cx="169.6" cy="90.5" r=".3"/>
<circle cx="169.6" cy="84.2" r=".3"/>
<circle cx="169.6" cy="80.3" r=".3"/>
<circle cx="169.6" cy="88.9" r=".3"/>
<circle cx="170.4" cy="90.5" r=".3"/>
<circle cx="170.4" cy="81.1" r=".3"/>
<circle cx="170.4" cy="87.4" r=".3"/>
<circle cx="170.4" cy="88.2" r=".3"/>
<circle cx="170.4" cy="81.9" r=".3"/>
<circle cx="170.4" cy="92.1" r=".31"/>
<circle cx="171.2" cy="86.6" r=".3"/>
<circle cx="171.2" cy="92.1" r=".29"/>
<circle cx="171.2" cy="85" r=".32"/>
<circle cx="171.2" cy="91.3" r=".32"/>
<circle cx="171.2" cy="89.7" r=".31"/>
<circle cx="171.2" cy="81.1" r=".34"/>
<circle cx="172" cy="91.3" r=".3"/>
<circle cx="172" cy="90.5" r=".32"/>
<circle cx="172" cy="84.2" r=".31"/>
<circle cx="172" cy="92.8" r=".3"/>
<circle cx="172" cy="80.3" r=".3"/>
<circle cx="172" cy="86.6" r=".3"/>
<circle cx="172.7" cy="84.2" r=".3"/>
<circle cx="172.7" cy="87.4" r=".3"/>
<circle cx="172.8" cy="88.2" r=".3"/>
<circle cx="172.8" cy="81.9" r=".3"/>
<circle cx="172.8" cy="89.7" r=".31"/>
<circle cx="172.8" cy="80.3" r=".31"/>
<circle cx="172.8" cy="92.8" r=".31"/>
<circle cx="172.8" cy="83.4" r=".31"/>
<circle cx="172.8" cy="92.1" r=".3"/>
<circle cx="173.5" cy="81.1" r=".31"/>
<circle cx="173.5" cy="90.5" r=".3"/>
<circle cx="173.5" cy="87.4" r=".3"/>
<circle cx="174.3" cy="83.4" r=".31"/>
<circle cx="174.3" cy="92.8" r=".31"/>
<circle cx="174.3" cy="89.7" r=".31"/>
<circle cx="174.3" cy="80.3" r=".31"/>
<circle cx="174.3" cy="87.4" r=".31"/>
<circle cx="174.3" cy="84.2" r=".31"/>
<circle cx="174.3" cy="92.1" r=".3"/>
<circle cx="175.1" cy="86.6" r=".31"/>
<circle cx="175.1" cy="82.7" r=".3"/>
<circle cx="175.1" cy="88.2" r=".3"/>
<circle cx="175.1" cy="81.1" r=".31"/>
<circle cx="175.1" cy="92.8" r=".3"/>
<circle cx="175.1" cy="89.7" r=".3"/>
<circle cx="175.9" cy="91.3" r=".3"/>
<circle cx="175.9" cy="81.1" r=".3"/>
<circle cx="175.9" cy="90.5" r=".3"/>
<circle cx="175.9" cy="87.4" r=".3"/>
<circle cx="175.9" cy="85" r=".3"/>
<circle cx="175.9" cy="88.2" r=".29"/>
<circle cx="175.9" cy="83.4" r=".3"/>
<circle cx="175.9" cy="85.8" r=".3"/>
<circle cx="176.6" cy="90.5" r=".31"/>
<circle cx="176.6" cy="84.2" r=".31"/>
<circle cx="176.6" cy="87.4" r=".31"/>
<circle cx="176.6" cy="91.3" r=".3"/>
<circle cx="176.7" cy="92.1" r=".3"/>
<circle cx="176.7" cy="88.9" r=".3"/>
<circle cx="177.4" cy="92.1" r=".29"/>
<circle cx="177.4" cy="82.7" r=".29"/>
<circle cx="177.4" cy="88.9" r=".29"/>
<circle cx="177.5" cy="86.6" r=".31"/>
<circle cx="177.5" cy="80.3" r=".31"/>
<circle cx="177.5" cy="84.2" r=".34"/>
<circle cx="178.2" cy="87.4" r=".31"/>
<circle cx="178.2" cy="81.1" r=".32"/>
<circle cx="178.2" cy="90.5" r=".32"/>
<circle cx="178.2" cy="85" r=".31"/>
<circle cx="178.2" cy="83.4" r=".3"/>
<circle cx="178.2" cy="89.7" r=".3"/>
<circle cx="178.2" cy="88.2" r=".3"/>
<circle cx="178.3" cy="86.6" r=".29"/>
<circle cx="179" cy="81.1" r=".3"/>
<circle cx="179" cy="90.5" r=".3"/>
<circle cx="179" cy="88.2" r=".3"/>
<circle cx="179" cy="88.9" r=".3"/>
<circle cx="179.8" cy="84.2" r=".31"/>
<circle cx="179.8" cy="81.9" r=".3"/>
<circle cx="179.8" cy="82.7" r=".28"/>
<circle cx="179.8" cy="88.9" r=".3"/>
<circle cx="180.6" cy="85" r=".31"/>
<circle cx="180.6" cy="86.6" r=".31"/>
<circle cx="180.6" cy="89.7" r=".31"/>
<circle cx="180.6" cy="81.1" r=".31"/>
<circle cx="180.6" cy="80.3" r=".31"/>
<circle cx="180.6" cy="84.2" r=".31"/>
<circle cx="181.4" cy="85.8" r=".3"/>
<circle cx="181.4" cy="87.4" r=".31"/>
<circle cx="181.4" cy="83.4" r=".3"/>
<circle cx="181.4" cy="88.2" r=".3"/>
<circle cx="181.4" cy="81.1" r=".31"/>
<circle cx="181.4" cy="85" r=".3"/>
<circle cx="182.1" cy="81.9" r=".31"/>
<circle cx="182.2" cy="86.6" r=".31"/>
<circle cx="182.2" cy="83.4" r=".3"/>
<circle cx="182.2" cy="85.8" r=".3"/>
<circle cx="183" cy="82.7" r=".3"/>
<circle cx="172" cy="115.6" r=".31"/>
</g>
</svg>
